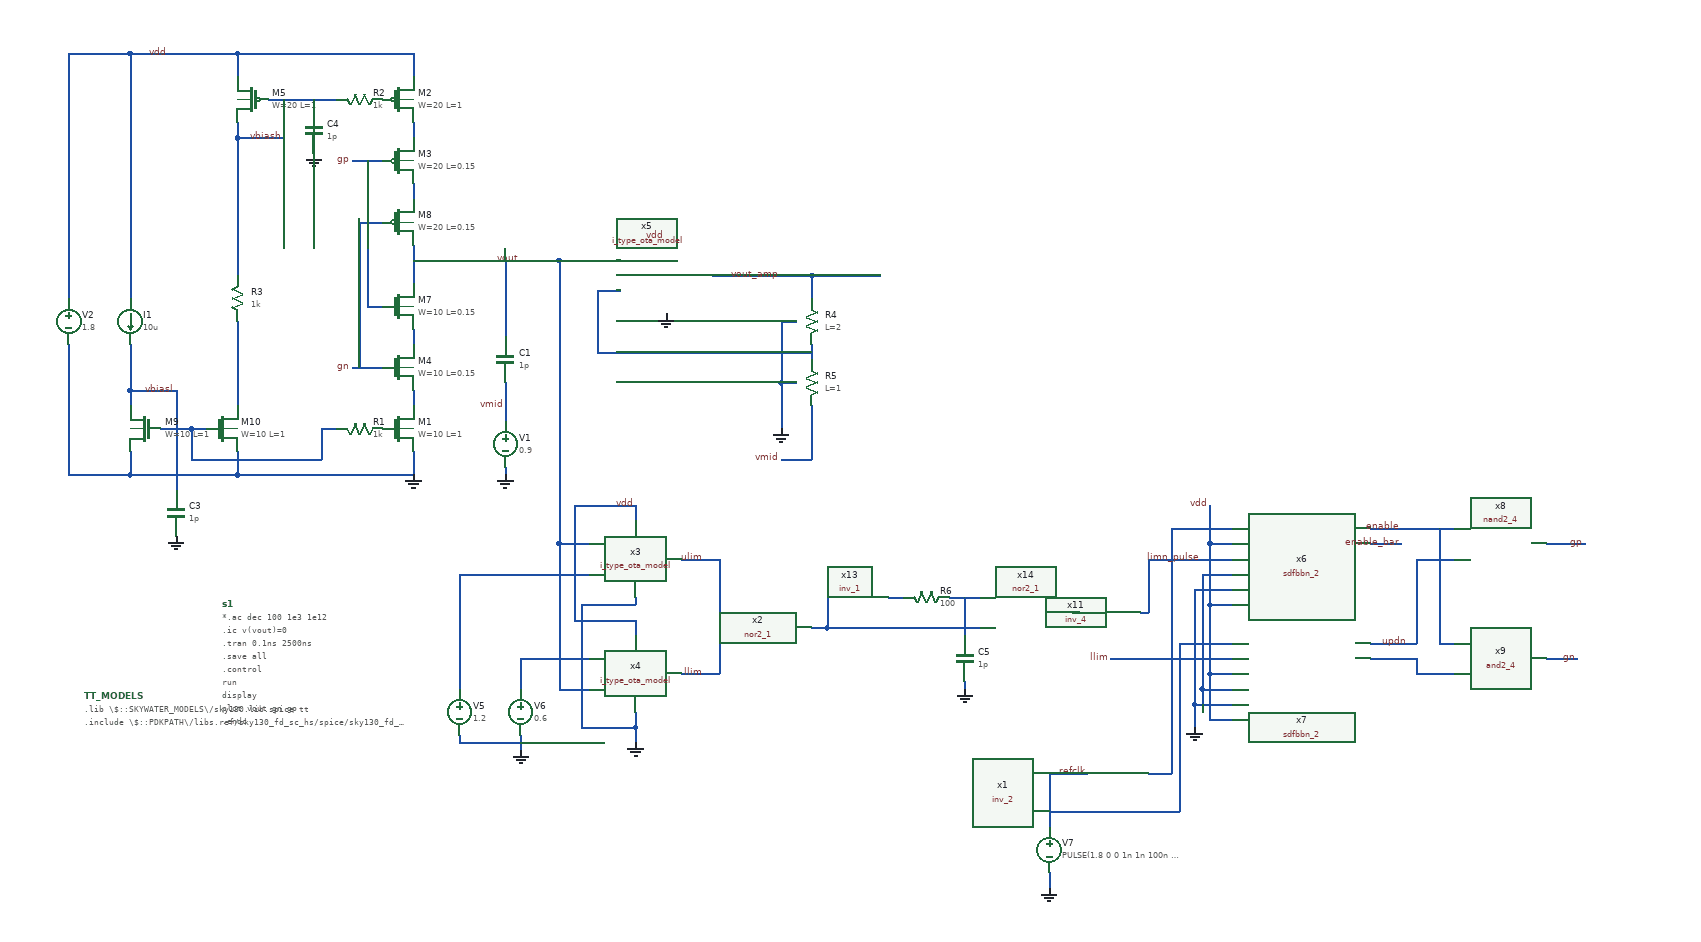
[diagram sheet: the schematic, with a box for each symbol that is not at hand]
v {xschem version=3.1.0 file_version=1.2
}
G {}
K {}
V {}
S {}
E {}
N 440 -200 440 -180 {
lab=vout}
N 440 -10 440 0 {
lab=GND}
N 320 -460 320 -440 {
lab=#net1}
N 320 -110 320 -90 {
lab=#net2}
N 440 -280 440 -200 {
lab=vout}
N 320 -190 320 -170 {
lab=#net3}
N 320 -380 320 -360 {
lab=#net4}
N 320 -300 320 -250 {
lab=vout}
N 320 -280 390 -280 {
lab=vout}
N 250 -330 250 -140 {
lab=gn}
N 260 -410 260 -220 {
lab=gp}
N 610 190 610 210 {
lab=vdd}
N 530 190 610 190 {
lab=vdd}
N 530 40 530 190 {
lab=vdd}
N 530 40 610 40 {
lab=vdd}
N 610 40 610 60 {
lab=vdd}
N 610 160 610 170 {
lab=GND}
N 540 170 610 170 {
lab=GND}
N 540 170 540 330 {
lab=GND}
N 540 330 610 330 {
lab=GND}
N 610 310 610 330 {
lab=GND}
N 610 330 610 350 {
lab=GND}
N 470 130 550 130 {
lab=#net5}
N 510 90 510 280 {
lab=vout}
N 510 280 550 280 {
lab=vout}
N 460 240 460 280 {
lab=#net6}
N 380 130 380 280 {
lab=#net5}
N 380 130 470 130 {
lab=#net5}
N 460 240 550 240 {
lab=#net6}
N 460 340 460 360 {
lab=GND}
N 380 340 380 350 {
lab=GND}
N 380 350 460 350 {
lab=GND}
N 700 110 710 110 {
lab=ulim}
N 700 260 710 260 {
lab=llim}
N 1360 90 1380 90 {
lab=vdd}
N 1150 520 1150 540 {
lab=GND}
N 1150 390 1150 460 {
lab=refclk}
N 1570 70 1620 70 {
lab=enable}
N 1370 240 1390 240 {
lab=llim}
N 1570 240 1600 240 {
lab=#net7}
N 1570 220 1630 220 {
lab=updn}
N 1380 90 1390 90 {
lab=vdd}
N 1620 70 1680 70 {
lab=enable}
N 1660 70 1660 220 {
lab=enable}
N 1660 220 1680 220 {
lab=enable}
N 1640 110 1680 110 {
lab=updn}
N 1630 110 1630 220 {
lab=updn}
N 1630 110 1640 110 {
lab=updn}
N 1600 240 1630 240 {
lab=#net7}
N 1630 240 1630 260 {
lab=#net7}
N 1630 260 1680 260 {
lab=#net7}
N 1800 90 1850 90 {
lab=gp}
N 1800 240 1840 240 {
lab=gn}
N 1350 280 1390 280 {
lab=GND}
N 1350 130 1350 280 {
lab=GND}
N 1350 130 1390 130 {
lab=GND}
N 1340 150 1390 150 {
lab=GND}
N 1340 150 1340 300 {
lab=GND}
N 1340 300 1390 300 {
lab=GND}
N 1340 300 1340 330 {
lab=GND}
N 1330 70 1390 70 {
lab=#net8}
N 1360 40 1360 90 {
lab=vdd}
N 1360 170 1390 170 {
lab=vdd}
N 1280 110 1390 110 {
lab=limn_pulse}
N 1310 70 1310 130 {
lab=#net8}
N 1310 70 1330 70 {
lab=#net8}
N 390 -280 460 -280 {
lab=vout}
N 510 90 550 90 {
lab=vout}
N 510 -280 510 90 {
lab=vout}
N 460 -280 510 -280 {
lab=vout}
N 440 -120 440 -70 {
lab=vmid}
N 670 110 700 110 {
lab=ulim}
N 670 260 700 260 {
lab=llim}
N 1570 90 1610 90 {
lab=enable_bar}
N 1350 280 1350 300 {
lab=GND}
N 1040 160 1040 210 {
lab=#net9}
N 1040 270 1040 280 {
lab=GND}
N 860 200 1060 200 {
lab=#net10}
N 860 160 860 200 {
lab=#net10}
N 940 160 960 160 {
lab=#net11}
N 1020 160 1060 160 {
lab=#net9}
N 1360 90 1360 170 {
lab=vdd}
N 710 260 720 260 {
lab=llim}
N 710 110 720 110 {
lab=ulim}
N 1150 390 1200 390 {
lab=refclk}
N 1150 440 1320 440 {
lab=refclk}
N 1310 130 1310 390 {
lab=#net8}
N 1320 220 1320 440 {
lab=refclk}
N 1320 220 1390 220 {
lab=refclk}
N 1360 260 1390 260 {
lab=vdd}
N 1360 170 1360 260 {
lab=vdd}
N 1360 260 1360 320 {
lab=vdd}
N 1360 320 1390 320 {
lab=vdd}
N 1230 240 1370 240 {
lab=llim}
N 720 220 720 260 {
lab=llim}
N 720 110 720 180 {
lab=ulim}
N 840 200 860 200 {
lab=#net10}
N 1180 180 1190 180 {
lab=#net12}
N 1270 180 1280 180 {
lab=limn_pulse}
N 1280 110 1280 180 {
lab=limn_pulse}
N 1280 390 1310 390 {
lab=#net8}
N 320 -550 320 -520 {
lab=vdd}
N 250 -330 280 -330 {
lab=gn}
N 240 -140 280 -140 {
lab=gn}
N 240 -410 280 -410 {
lab=gp}
N 260 -220 280 -220 {
lab=gp}
N 190 -490 190 -480 {
lab=vbiash}
N 130 -490 220 -490 {
lab=vbiash}
N 150 -490 150 -440 {
lab=vbiash}
N 90 -440 150 -440 {
lab=vbiash}
N 90 -460 90 -440 {
lab=vbiash}
N 90 -550 90 -520 {
lab=vdd}
N 90 -550 320 -550 {
lab=vdd}
N 200 -60 220 -60 {
lab=vbiasl}
N 30 -60 50 -60 {
lab=vbiasl}
N 90 -30 90 0 {
lab=GND}
N 320 -30 320 0 {
lab=GND}
N 90 0 320 0 {
lab=GND}
N 30 -60 30 -20 {
lab=vbiasl}
N 30 -20 200 -20 {
lab=vbiasl}
N 200 -60 200 -20 {
lab=vbiasl}
N -10 -60 30 -60 {
lab=vbiasl}
N -50 -30 -50 0 {
lab=GND}
N -50 0 90 0 {
lab=GND}
N 10 -110 10 -60 {
lab=vbiasl}
N -50 -110 10 -110 {
lab=vbiasl}
N -50 -110 -50 -90 {
lab=vbiasl}
N 10 -60 10 20 {
lab=vbiasl}
N -50 -170 -50 -110 {
lab=vbiasl}
N -50 -550 -50 -230 {
lab=vdd}
N -50 -550 90 -550 {
lab=vdd}
N -130 -170 -130 0 {
lab=GND}
N -130 0 -50 0 {
lab=GND}
N -130 -550 -130 -230 {
lab=vdd}
N -130 -550 -50 -550 {
lab=vdd}
N 90 -200 90 -90 {
lab=#net13}
N 90 -440 90 -260 {
lab=vbiash}
N 840 -170 840 -150 {
lab=#net14}
N 800 -200 820 -200 {
lab=GND}
N 800 -200 800 -120 {
lab=GND}
N 800 -120 820 -120 {
lab=GND}
N 800 -120 800 -60 {
lab=GND}
N 840 -260 840 -230 {
lab=vout_amp}
N 710 -260 840 -260 {
lab=vout_amp}
N 510 -280 590 -280 {
lab=vout}
N 560 -240 590 -240 {
lab=#net14}
N 560 -160 840 -160 {
lab=#net14}
N 560 -240 560 -160 {
lab=#net14}
N 800 -20 840 -20 {
lab=vmid}
N 840 -90 840 -20 {
lab=vmid}
N 840 -260 930 -260 {
lab=vout_amp}
C {sky130_fd_pr/nfet3_01v8.sym} 300 -60 0 0 {name=M1
L=1
W=10
body=GND
nf=1
mult=1
ad="'int((nf+1)/2) * W/nf * 0.29'" 
pd="'2*int((nf+1)/2) * (W/nf + 0.29)'"
as="'int((nf+2)/2) * W/nf * 0.29'" 
ps="'2*int((nf+2)/2) * (W/nf + 0.29)'"
nrd="'0.29 / W'" nrs="'0.29 / W'"
sa=0 sb=0 sd=0
model=nfet_01v8
spiceprefix=X
}
C {sky130_fd_pr/pfet3_01v8.sym} 300 -490 0 0 {name=M2
L=1
W=20
body=VDD
nf=1
mult=1
ad="'int((nf+1)/2) * W/nf * 0.29'" 
pd="'2*int((nf+1)/2) * (W/nf + 0.29)'"
as="'int((nf+2)/2) * W/nf * 0.29'" 
ps="'2*int((nf+2)/2) * (W/nf + 0.29)'"
nrd="'0.29 / W'" nrs="'0.29 / W'"
sa=0 sb=0 sd=0
model=pfet_01v8
spiceprefix=X
}
C {sky130_fd_pr/pfet3_01v8.sym} 300 -410 0 0 {name=M3
L=0.15
W=20
body=VDD
nf=1
mult=1
ad="'int((nf+1)/2) * W/nf * 0.29'" 
pd="'2*int((nf+1)/2) * (W/nf + 0.29)'"
as="'int((nf+2)/2) * W/nf * 0.29'" 
ps="'2*int((nf+2)/2) * (W/nf + 0.29)'"
nrd="'0.29 / W'" nrs="'0.29 / W'"
sa=0 sb=0 sd=0
model=pfet_01v8
spiceprefix=X
}
C {sky130_fd_pr/nfet3_01v8.sym} 300 -140 0 0 {name=M4
L=0.15
W=10
body=GND
nf=1
mult=1
ad="'int((nf+1)/2) * W/nf * 0.29'" 
pd="'2*int((nf+1)/2) * (W/nf + 0.29)'"
as="'int((nf+2)/2) * W/nf * 0.29'" 
ps="'2*int((nf+2)/2) * (W/nf + 0.29)'"
nrd="'0.29 / W'" nrs="'0.29 / W'"
sa=0 sb=0 sd=0
model=nfet_01v8
spiceprefix=X
}
C {devices/gnd.sym} 320 0 0 0 {name=l1 lab=GND}
C {devices/capa.sym} 440 -150 0 0 {name=C1
m=1
value=1p
footprint=1206
device="ceramic capacitor"}
C {devices/gnd.sym} 440 0 0 0 {name=l2 lab=GND}
C {devices/vsource.sym} 440 -40 0 0 {name=V1 value=0.9}
C {devices/vsource.sym} -130 -200 0 0 {name=V2 value=1.8}
C {sky130_fd_pr/pfet3_01v8.sym} 110 -490 0 1 {name=M5
L=1
W=20
body=VDD
nf=1
mult=1
ad="'int((nf+1)/2) * W/nf * 0.29'" 
pd="'2*int((nf+1)/2) * (W/nf + 0.29)'"
as="'int((nf+2)/2) * W/nf * 0.29'" 
ps="'2*int((nf+2)/2) * (W/nf + 0.29)'"
nrd="'0.29 / W'" nrs="'0.29 / W'"
sa=0 sb=0 sd=0
model=pfet_01v8
spiceprefix=X
}
C {devices/isource.sym} -50 -200 0 0 {name=I1 value=10u}
C {devices/lab_wire.sym} 0 -550 0 0 {name=p1 sig_type=std_logic lab=vdd}
C {devices/lab_wire.sym} 460 -280 0 0 {name=p2 sig_type=std_logic lab=vout}
C {devices/lab_wire.sym} 240 -140 0 0 {name=p3 sig_type=std_logic lab=gn}
C {devices/code.sym} -110 290 0 0 {name=TT_MODELS only_toplevel=false
format="tcleval(@value )" value=".lib \\\\$::SKYWATER_MODELS\\\\/sky130.lib.spice tt
.include \\\\$::PDKPATH\\\\/libs.ref/sky130_fd_sc_hs/spice/sky130_fd_sc_hs.spice"}
C {devices/code_shown.sym} 70 170 0 0 {name=s1
only_toplevel=false
value="
*.ac dec 100 1e3 1e12
.ic v(vout)=0
.tran 0.1ns 2500ns
.save all
.control
run
display
plot vout gn gp
.endc
"}
C {devices/lab_wire.sym} 240 -410 0 0 {name=p4 sig_type=std_logic lab=gp}
C {devices/lab_wire.sym} 10 -110 0 0 {name=p5 sig_type=std_logic lab=vbiasl}
C {devices/lab_wire.sym} 150 -440 0 0 {name=p6 sig_type=std_logic lab=vbiash}
C {devices/res.sym} 250 -60 1 0 {name=R1
value=1k
footprint=1206
device=resistor
m=1}
C {devices/res.sym} 250 -490 1 0 {name=R2
value=1k
footprint=1206
device=resistor
m=1}
C {sky130_fd_pr/nfet3_01v8.sym} 300 -220 0 0 {name=M7
L=0.15
W=10
body=GND
nf=1
mult=1
ad="'int((nf+1)/2) * W/nf * 0.29'" 
pd="'2*int((nf+1)/2) * (W/nf + 0.29)'"
as="'int((nf+2)/2) * W/nf * 0.29'" 
ps="'2*int((nf+2)/2) * (W/nf + 0.29)'"
nrd="'0.29 / W'" nrs="'0.29 / W'"
sa=0 sb=0 sd=0
model=nfet_01v8
spiceprefix=X
}
C {sky130_fd_pr/pfet3_01v8.sym} 300 -330 0 0 {name=M8
L=0.15
W=20
body=VDD
nf=1
mult=1
ad="'int((nf+1)/2) * W/nf * 0.29'" 
pd="'2*int((nf+1)/2) * (W/nf + 0.29)'"
as="'int((nf+2)/2) * W/nf * 0.29'" 
ps="'2*int((nf+2)/2) * (W/nf + 0.29)'"
nrd="'0.29 / W'" nrs="'0.29 / W'"
sa=0 sb=0 sd=0
model=pfet_01v8
spiceprefix=X
}
C {devices/lab_wire.sym} 610 40 0 0 {name=p7 sig_type=std_logic lab=vdd}
C {devices/gnd.sym} 610 350 0 0 {name=l5 lab=GND}
C {devices/lab_wire.sym} 700 110 0 0 {name=p8 sig_type=std_logic lab=ulim}
C {devices/lab_wire.sym} 700 260 0 0 {name=p9 sig_type=std_logic lab=llim}
C {devices/vsource.sym} 380 310 0 0 {name=V5 value="1.2"}
C {devices/vsource.sym} 460 310 0 0 {name=V6 value="0.6"}
C {devices/gnd.sym} 460 360 0 0 {name=l7 lab=GND}
C {sky130_stdcells/sdfbbn_2.sym} 1480 120 0 0 {name=x6 VGND=gnd VNB=gnd VPB=vdd VPWR=vdd prefix=sky130_fd_sc_hs__ 
}
C {devices/lab_wire.sym} 1360 40 0 0 {name=p11 sig_type=std_logic lab=vdd}
C {devices/vsource.sym} 1150 490 0 0 {name=V7 value="PULSE(1.8 0 0 1n 1n 100n 200n)"}
C {devices/gnd.sym} 1150 540 0 0 {name=l8 lab=GND}
C {devices/lab_wire.sym} 1200 390 0 0 {name=p12 sig_type=std_logic lab=refclk}
C {devices/lab_wire.sym} 1610 70 0 0 {name=p13 sig_type=std_logic lab=enable}
C {sky130_stdcells/sdfbbn_2.sym} 1480 270 0 0 {name=x7 VGND=gnd VNB=gnd VPB=vdd VPWR=vdd prefix=sky130_fd_sc_hs__ 
}
C {devices/lab_wire.sym} 1620 220 0 0 {name=p15 sig_type=std_logic lab=updn}
C {sky130_stdcells/nand2_4.sym} 1740 90 0 0 {name=x8 VGND=gnd VNB=gnd VPB=vdd VPWR=vdd prefix=sky130_fd_sc_hs__ }
C {sky130_stdcells/and2_4.sym} 1740 240 0 0 {name=x9 VGND=gnd VNB=gnd VPB=vdd VPWR=vdd prefix=sky130_fd_sc_hs__ 
}
C {devices/lab_wire.sym} 1850 90 0 0 {name=p16 sig_type=std_logic lab=gp}
C {devices/lab_wire.sym} 1840 240 0 0 {name=p17 sig_type=std_logic lab=gn}
C {devices/gnd.sym} 1340 330 0 0 {name=l9 lab=GND}
C {devices/lab_wire.sym} 440 -90 0 0 {name=p18 sig_type=std_logic lab=vmid}
C {devices/lab_wire.sym} 1610 90 0 0 {name=p20 sig_type=std_logic lab=enable_bar}
C {devices/lab_wire.sym} 1350 110 0 0 {name=p21 sig_type=std_logic lab=limn_pulse}
C {sky130_stdcells/inv_2.sym} 1240 390 0 0 {name=x1 VGND=gnd VNB=gnd VPB=vdd VPWR=vdd prefix=sky130_fd_sc_hs__ 
}
C {devices/res.sym} 990 160 1 0 {name=R6
value=100
footprint=1206
device=resistor
m=1}
C {devices/capa.sym} 1040 240 0 0 {name=C5
m=1
value=1p
footprint=1206
device="ceramic capacitor"}
C {devices/gnd.sym} 1040 280 0 0 {name=l10 lab=GND}
C {sky130_stdcells/inv_1.sym} 900 160 0 0 {name=x13 VGND=gnd VNB=gnd VPB=vdd VPWR=vdd prefix=sky130_fd_sc_hs__ 
}
C {devices/lab_wire.sym} 1230 240 0 0 {name=p22 sig_type=std_logic lab=llim}
C {sky130_stdcells/nor2_1.sym} 1120 180 0 0 {name=x14 VGND=gnd VNB=gnd VPB=vdd VPWR=vdd prefix=sky130_fd_sc_hs__ 
}
C {sky130_stdcells/nor2_1.sym} 780 200 0 0 {name=x2 VGND=gnd VNB=gnd VPB=vdd VPWR=vdd prefix=sky130_fd_sc_hs__ 
}
C {/home/andylithia/openmpw/pdk_1/volare/sky130/versions/3af133706e554a740cfe60f21e773d9eaa41838c.bk1/sky130A/libs.tech/xschem/sky130_stdcells/inv_4.sym} 1230 180 0 0 {name=x11 VGND=gnd VNB=gnd VPB=vdd VPWR=vdd prefix=sky130_fd_sc_hs__ 
}
C {devices/capa.sym} 190 -450 0 0 {name=C4
m=1
value=1p
footprint=1206
device="ceramic capacitor"}
C {devices/gnd.sym} 190 -420 0 0 {name=l3 lab=GND}
C {sky130_fd_pr/nfet3_01v8.sym} 70 -60 0 0 {name=M10
L=1
W=10
body=GND
nf=1
mult=1
ad="'int((nf+1)/2) * W/nf * 0.29'" 
pd="'2*int((nf+1)/2) * (W/nf + 0.29)'"
as="'int((nf+2)/2) * W/nf * 0.29'" 
ps="'2*int((nf+2)/2) * (W/nf + 0.29)'"
nrd="'0.29 / W'" nrs="'0.29 / W'"
sa=0 sb=0 sd=0
model=nfet_01v8
spiceprefix=X
}
C {sky130_fd_pr/nfet3_01v8.sym} -30 -60 0 1 {name=M9
L=1
W=10
body=GND
nf=1
mult=1
ad="'int((nf+1)/2) * W/nf * 0.29'" 
pd="'2*int((nf+1)/2) * (W/nf + 0.29)'"
as="'int((nf+2)/2) * W/nf * 0.29'" 
ps="'2*int((nf+2)/2) * (W/nf + 0.29)'"
nrd="'0.29 / W'" nrs="'0.29 / W'"
sa=0 sb=0 sd=0
model=nfet_01v8
spiceprefix=X
}
C {devices/capa.sym} 10 50 0 0 {name=C3
m=1
value=1p
footprint=1206
device="ceramic capacitor"}
C {devices/gnd.sym} 10 80 0 0 {name=l11 lab=GND}
C {devices/res.sym} 90 -230 2 0 {name=R3
value=1k
footprint=1206
device=resistor
m=1}
C {i_type_ota_model.sym} 610 110 0 0 {name=x3}
C {i_type_ota_model.sym} 610 260 0 0 {name=x4}
C {i_type_ota_model.sym} 650 -260 0 0 {name=x5}
C {devices/lab_wire.sym} 650 -310 0 0 {name=p10 sig_type=std_logic lab=vdd}
C {devices/gnd.sym} 650 -210 0 0 {name=l4 lab=GND}
C {sky130_fd_pr/res_xhigh_po_0p35.sym} 840 -200 0 0 {name=R4
L=2
model=res_xhigh_po_0p35
spiceprefix=X
mult=1}
C {sky130_fd_pr/res_xhigh_po_0p35.sym} 840 -120 0 0 {name=R5
L=1
model=res_xhigh_po_0p35
spiceprefix=X
mult=1}
C {devices/gnd.sym} 800 -60 0 0 {name=l6 lab=GND}
C {devices/lab_wire.sym} 800 -20 0 0 {name=p14 sig_type=std_logic lab=vmid}
C {devices/lab_wire.sym} 800 -260 0 0 {name=p19 sig_type=std_logic lab=vout_amp}
